VERSION 5.7 ;
  NOWIREEXTENSIONATPIN ON ;
  DIVIDERCHAR "/" ;
  BUSBITCHARS "[]" ;
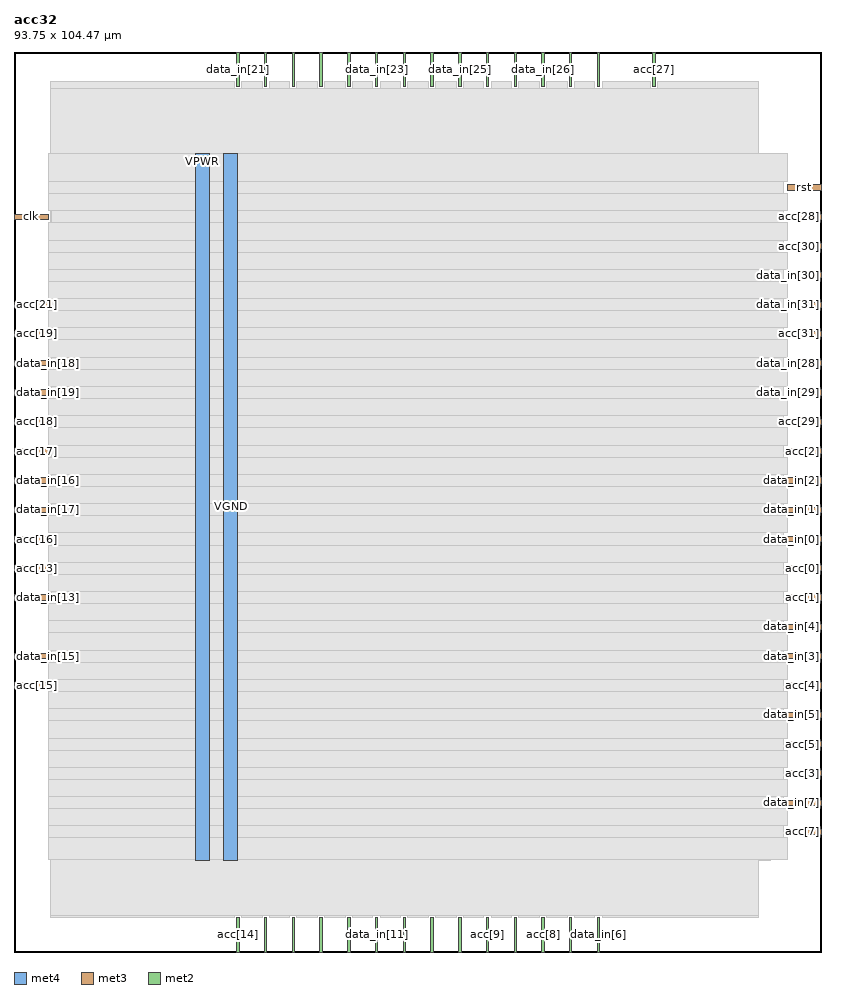
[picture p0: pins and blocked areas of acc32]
MACRO acc32
  CLASS BLOCK ;
  FOREIGN acc32 ;
  ORIGIN 0.000 0.000 ;
  SIZE 93.750 BY 104.470 ;
  PIN VGND
    DIRECTION INOUT ;
    USE GROUND ;
    PORT
      LAYER met4 ;
        RECT 24.340 10.640 25.940 92.720 ;
    END
  END VGND
  PIN VPWR
    DIRECTION INOUT ;
    USE POWER ;
    PORT
      LAYER met4 ;
        RECT 21.040 10.640 22.640 92.720 ;
    END
  END VPWR
  PIN acc[0]
    DIRECTION OUTPUT ;
    USE SIGNAL ;
    ANTENNADIFFAREA 0.445500 ;
    PORT
      LAYER met3 ;
        RECT 89.750 44.240 93.750 44.840 ;
    END
  END acc[0]
  PIN acc[10]
    DIRECTION OUTPUT ;
    USE SIGNAL ;
    ANTENNADIFFAREA 0.445500 ;
    PORT
      LAYER met2 ;
        RECT 35.510 0.000 35.790 4.000 ;
    END
  END acc[10]
  PIN acc[11]
    DIRECTION OUTPUT ;
    USE SIGNAL ;
    ANTENNADIFFAREA 0.445500 ;
    PORT
      LAYER met2 ;
        RECT 45.170 0.000 45.450 4.000 ;
    END
  END acc[11]
  PIN acc[12]
    DIRECTION OUTPUT ;
    USE SIGNAL ;
    ANTENNADIFFAREA 0.445500 ;
    PORT
      LAYER met2 ;
        RECT 48.390 0.000 48.670 4.000 ;
    END
  END acc[12]
  PIN acc[13]
    DIRECTION OUTPUT ;
    USE SIGNAL ;
    ANTENNADIFFAREA 0.445500 ;
    PORT
      LAYER met3 ;
        RECT 0.000 44.240 4.000 44.840 ;
    END
  END acc[13]
  PIN acc[14]
    DIRECTION OUTPUT ;
    USE SIGNAL ;
    ANTENNADIFFAREA 0.445500 ;
    PORT
      LAYER met2 ;
        RECT 25.850 0.000 26.130 4.000 ;
    END
  END acc[14]
  PIN acc[15]
    DIRECTION OUTPUT ;
    USE SIGNAL ;
    ANTENNADIFFAREA 0.445500 ;
    PORT
      LAYER met3 ;
        RECT 0.000 30.640 4.000 31.240 ;
    END
  END acc[15]
  PIN acc[16]
    DIRECTION OUTPUT ;
    USE SIGNAL ;
    ANTENNADIFFAREA 0.445500 ;
    PORT
      LAYER met3 ;
        RECT 0.000 47.640 4.000 48.240 ;
    END
  END acc[16]
  PIN acc[17]
    DIRECTION OUTPUT ;
    USE SIGNAL ;
    ANTENNADIFFAREA 0.445500 ;
    PORT
      LAYER met3 ;
        RECT 0.000 57.840 4.000 58.440 ;
    END
  END acc[17]
  PIN acc[18]
    DIRECTION OUTPUT ;
    USE SIGNAL ;
    ANTENNADIFFAREA 0.445500 ;
    PORT
      LAYER met3 ;
        RECT 0.000 61.240 4.000 61.840 ;
    END
  END acc[18]
  PIN acc[19]
    DIRECTION OUTPUT ;
    USE SIGNAL ;
    ANTENNADIFFAREA 0.445500 ;
    PORT
      LAYER met3 ;
        RECT 0.000 71.440 4.000 72.040 ;
    END
  END acc[19]
  PIN acc[1]
    DIRECTION OUTPUT ;
    USE SIGNAL ;
    ANTENNADIFFAREA 0.445500 ;
    PORT
      LAYER met3 ;
        RECT 89.750 40.840 93.750 41.440 ;
    END
  END acc[1]
  PIN acc[20]
    DIRECTION OUTPUT ;
    USE SIGNAL ;
    ANTENNADIFFAREA 0.445500 ;
    PORT
      LAYER met2 ;
        RECT 35.510 100.470 35.790 104.470 ;
    END
  END acc[20]
  PIN acc[21]
    DIRECTION OUTPUT ;
    USE SIGNAL ;
    ANTENNADIFFAREA 0.445500 ;
    PORT
      LAYER met3 ;
        RECT 0.000 74.840 4.000 75.440 ;
    END
  END acc[21]
  PIN acc[22]
    DIRECTION OUTPUT ;
    USE SIGNAL ;
    ANTENNADIFFAREA 0.445500 ;
    PORT
      LAYER met2 ;
        RECT 29.070 100.470 29.350 104.470 ;
    END
  END acc[22]
  PIN acc[23]
    DIRECTION OUTPUT ;
    USE SIGNAL ;
    ANTENNADIFFAREA 0.445500 ;
    PORT
      LAYER met2 ;
        RECT 45.170 100.470 45.450 104.470 ;
    END
  END acc[23]
  PIN acc[24]
    DIRECTION OUTPUT ;
    USE SIGNAL ;
    ANTENNADIFFAREA 0.445500 ;
    PORT
      LAYER met2 ;
        RECT 54.830 100.470 55.110 104.470 ;
    END
  END acc[24]
  PIN acc[25]
    DIRECTION OUTPUT ;
    USE SIGNAL ;
    ANTENNADIFFAREA 0.445500 ;
    PORT
      LAYER met2 ;
        RECT 48.390 100.470 48.670 104.470 ;
    END
  END acc[25]
  PIN acc[26]
    DIRECTION OUTPUT ;
    USE SIGNAL ;
    ANTENNADIFFAREA 0.445500 ;
    PORT
      LAYER met2 ;
        RECT 67.710 100.470 67.990 104.470 ;
    END
  END acc[26]
  PIN acc[27]
    DIRECTION OUTPUT ;
    USE SIGNAL ;
    ANTENNADIFFAREA 0.445500 ;
    PORT
      LAYER met2 ;
        RECT 74.150 100.470 74.430 104.470 ;
    END
  END acc[27]
  PIN acc[28]
    DIRECTION OUTPUT ;
    USE SIGNAL ;
    ANTENNADIFFAREA 0.445500 ;
    PORT
      LAYER met3 ;
        RECT 89.750 85.040 93.750 85.640 ;
    END
  END acc[28]
  PIN acc[29]
    DIRECTION OUTPUT ;
    USE SIGNAL ;
    ANTENNADIFFAREA 0.445500 ;
    PORT
      LAYER met3 ;
        RECT 89.750 61.240 93.750 61.840 ;
    END
  END acc[29]
  PIN acc[2]
    DIRECTION OUTPUT ;
    USE SIGNAL ;
    ANTENNADIFFAREA 0.445500 ;
    PORT
      LAYER met3 ;
        RECT 89.750 57.840 93.750 58.440 ;
    END
  END acc[2]
  PIN acc[30]
    DIRECTION OUTPUT ;
    USE SIGNAL ;
    ANTENNADIFFAREA 0.445500 ;
    PORT
      LAYER met3 ;
        RECT 89.750 81.640 93.750 82.240 ;
    END
  END acc[30]
  PIN acc[31]
    DIRECTION OUTPUT ;
    USE SIGNAL ;
    ANTENNADIFFAREA 0.445500 ;
    PORT
      LAYER met3 ;
        RECT 89.750 71.440 93.750 72.040 ;
    END
  END acc[31]
  PIN acc[3]
    DIRECTION OUTPUT ;
    USE SIGNAL ;
    ANTENNADIFFAREA 0.445500 ;
    PORT
      LAYER met3 ;
        RECT 89.750 20.440 93.750 21.040 ;
    END
  END acc[3]
  PIN acc[4]
    DIRECTION OUTPUT ;
    USE SIGNAL ;
    ANTENNADIFFAREA 0.445500 ;
    PORT
      LAYER met3 ;
        RECT 89.750 30.640 93.750 31.240 ;
    END
  END acc[4]
  PIN acc[5]
    DIRECTION OUTPUT ;
    USE SIGNAL ;
    ANTENNADIFFAREA 0.445500 ;
    PORT
      LAYER met3 ;
        RECT 89.750 23.840 93.750 24.440 ;
    END
  END acc[5]
  PIN acc[6]
    DIRECTION OUTPUT ;
    USE SIGNAL ;
    ANTENNADIFFAREA 0.445500 ;
    PORT
      LAYER met2 ;
        RECT 64.490 0.000 64.770 4.000 ;
    END
  END acc[6]
  PIN acc[7]
    DIRECTION OUTPUT ;
    USE SIGNAL ;
    ANTENNADIFFAREA 0.445500 ;
    PORT
      LAYER met3 ;
        RECT 89.750 13.640 93.750 14.240 ;
    END
  END acc[7]
  PIN acc[8]
    DIRECTION OUTPUT ;
    USE SIGNAL ;
    ANTENNADIFFAREA 0.445500 ;
    PORT
      LAYER met2 ;
        RECT 61.270 0.000 61.550 4.000 ;
    END
  END acc[8]
  PIN acc[9]
    DIRECTION OUTPUT ;
    USE SIGNAL ;
    ANTENNADIFFAREA 0.445500 ;
    PORT
      LAYER met2 ;
        RECT 54.830 0.000 55.110 4.000 ;
    END
  END acc[9]
  PIN clk
    DIRECTION INPUT ;
    USE SIGNAL ;
    ANTENNAGATEAREA 0.852000 ;
    PORT
      LAYER met3 ;
        RECT 0.000 85.040 4.000 85.640 ;
    END
  END clk
  PIN data_in[0]
    DIRECTION INPUT ;
    USE SIGNAL ;
    ANTENNAGATEAREA 0.196500 ;
    PORT
      LAYER met3 ;
        RECT 89.750 47.640 93.750 48.240 ;
    END
  END data_in[0]
  PIN data_in[10]
    DIRECTION INPUT ;
    USE SIGNAL ;
    ANTENNAGATEAREA 0.196500 ;
    PORT
      LAYER met2 ;
        RECT 38.730 0.000 39.010 4.000 ;
    END
  END data_in[10]
  PIN data_in[11]
    DIRECTION INPUT ;
    USE SIGNAL ;
    ANTENNAGATEAREA 0.196500 ;
    PORT
      LAYER met2 ;
        RECT 41.950 0.000 42.230 4.000 ;
    END
  END data_in[11]
  PIN data_in[12]
    DIRECTION INPUT ;
    USE SIGNAL ;
    ANTENNAGATEAREA 0.196500 ;
    PORT
      LAYER met2 ;
        RECT 32.290 0.000 32.570 4.000 ;
    END
  END data_in[12]
  PIN data_in[13]
    DIRECTION INPUT ;
    USE SIGNAL ;
    ANTENNAGATEAREA 0.196500 ;
    PORT
      LAYER met3 ;
        RECT 0.000 40.840 4.000 41.440 ;
    END
  END data_in[13]
  PIN data_in[14]
    DIRECTION INPUT ;
    USE SIGNAL ;
    ANTENNAGATEAREA 0.196500 ;
    PORT
      LAYER met2 ;
        RECT 29.070 0.000 29.350 4.000 ;
    END
  END data_in[14]
  PIN data_in[15]
    DIRECTION INPUT ;
    USE SIGNAL ;
    ANTENNAGATEAREA 0.196500 ;
    PORT
      LAYER met3 ;
        RECT 0.000 34.040 4.000 34.640 ;
    END
  END data_in[15]
  PIN data_in[16]
    DIRECTION INPUT ;
    USE SIGNAL ;
    ANTENNAGATEAREA 0.196500 ;
    PORT
      LAYER met3 ;
        RECT 0.000 54.440 4.000 55.040 ;
    END
  END data_in[16]
  PIN data_in[17]
    DIRECTION INPUT ;
    USE SIGNAL ;
    ANTENNAGATEAREA 0.196500 ;
    PORT
      LAYER met3 ;
        RECT 0.000 51.040 4.000 51.640 ;
    END
  END data_in[17]
  PIN data_in[18]
    DIRECTION INPUT ;
    USE SIGNAL ;
    ANTENNAGATEAREA 0.196500 ;
    PORT
      LAYER met3 ;
        RECT 0.000 68.040 4.000 68.640 ;
    END
  END data_in[18]
  PIN data_in[19]
    DIRECTION INPUT ;
    USE SIGNAL ;
    ANTENNAGATEAREA 0.196500 ;
    PORT
      LAYER met3 ;
        RECT 0.000 64.640 4.000 65.240 ;
    END
  END data_in[19]
  PIN data_in[1]
    DIRECTION INPUT ;
    USE SIGNAL ;
    ANTENNAGATEAREA 0.196500 ;
    PORT
      LAYER met3 ;
        RECT 89.750 51.040 93.750 51.640 ;
    END
  END data_in[1]
  PIN data_in[20]
    DIRECTION INPUT ;
    USE SIGNAL ;
    ANTENNAGATEAREA 0.196500 ;
    PORT
      LAYER met2 ;
        RECT 38.730 100.470 39.010 104.470 ;
    END
  END data_in[20]
  PIN data_in[21]
    DIRECTION INPUT ;
    USE SIGNAL ;
    ANTENNAGATEAREA 0.196500 ;
    PORT
      LAYER met2 ;
        RECT 25.850 100.470 26.130 104.470 ;
    END
  END data_in[21]
  PIN data_in[22]
    DIRECTION INPUT ;
    USE SIGNAL ;
    ANTENNAGATEAREA 0.196500 ;
    PORT
      LAYER met2 ;
        RECT 32.290 100.470 32.570 104.470 ;
    END
  END data_in[22]
  PIN data_in[23]
    DIRECTION INPUT ;
    USE SIGNAL ;
    ANTENNAGATEAREA 0.196500 ;
    PORT
      LAYER met2 ;
        RECT 41.950 100.470 42.230 104.470 ;
    END
  END data_in[23]
  PIN data_in[24]
    DIRECTION INPUT ;
    USE SIGNAL ;
    ANTENNAGATEAREA 0.196500 ;
    PORT
      LAYER met2 ;
        RECT 58.050 100.470 58.330 104.470 ;
    END
  END data_in[24]
  PIN data_in[25]
    DIRECTION INPUT ;
    USE SIGNAL ;
    ANTENNAGATEAREA 0.196500 ;
    PORT
      LAYER met2 ;
        RECT 51.610 100.470 51.890 104.470 ;
    END
  END data_in[25]
  PIN data_in[26]
    DIRECTION INPUT ;
    USE SIGNAL ;
    ANTENNAGATEAREA 0.196500 ;
    PORT
      LAYER met2 ;
        RECT 61.270 100.470 61.550 104.470 ;
    END
  END data_in[26]
  PIN data_in[27]
    DIRECTION INPUT ;
    USE SIGNAL ;
    ANTENNAGATEAREA 0.196500 ;
    PORT
      LAYER met2 ;
        RECT 64.490 100.470 64.770 104.470 ;
    END
  END data_in[27]
  PIN data_in[28]
    DIRECTION INPUT ;
    USE SIGNAL ;
    ANTENNAGATEAREA 0.196500 ;
    PORT
      LAYER met3 ;
        RECT 89.750 68.040 93.750 68.640 ;
    END
  END data_in[28]
  PIN data_in[29]
    DIRECTION INPUT ;
    USE SIGNAL ;
    ANTENNAGATEAREA 0.196500 ;
    PORT
      LAYER met3 ;
        RECT 89.750 64.640 93.750 65.240 ;
    END
  END data_in[29]
  PIN data_in[2]
    DIRECTION INPUT ;
    USE SIGNAL ;
    ANTENNAGATEAREA 0.196500 ;
    PORT
      LAYER met3 ;
        RECT 89.750 54.440 93.750 55.040 ;
    END
  END data_in[2]
  PIN data_in[30]
    DIRECTION INPUT ;
    USE SIGNAL ;
    ANTENNAGATEAREA 0.196500 ;
    PORT
      LAYER met3 ;
        RECT 89.750 78.240 93.750 78.840 ;
    END
  END data_in[30]
  PIN data_in[31]
    DIRECTION INPUT ;
    USE SIGNAL ;
    ANTENNAGATEAREA 0.196500 ;
    PORT
      LAYER met3 ;
        RECT 89.750 74.840 93.750 75.440 ;
    END
  END data_in[31]
  PIN data_in[3]
    DIRECTION INPUT ;
    USE SIGNAL ;
    ANTENNAGATEAREA 0.213000 ;
    PORT
      LAYER met3 ;
        RECT 89.750 34.040 93.750 34.640 ;
    END
  END data_in[3]
  PIN data_in[4]
    DIRECTION INPUT ;
    USE SIGNAL ;
    ANTENNAGATEAREA 0.196500 ;
    PORT
      LAYER met3 ;
        RECT 89.750 37.440 93.750 38.040 ;
    END
  END data_in[4]
  PIN data_in[5]
    DIRECTION INPUT ;
    USE SIGNAL ;
    ANTENNAGATEAREA 0.196500 ;
    PORT
      LAYER met3 ;
        RECT 89.750 27.240 93.750 27.840 ;
    END
  END data_in[5]
  PIN data_in[6]
    DIRECTION INPUT ;
    USE SIGNAL ;
    ANTENNAGATEAREA 0.196500 ;
    PORT
      LAYER met2 ;
        RECT 67.710 0.000 67.990 4.000 ;
    END
  END data_in[6]
  PIN data_in[7]
    DIRECTION INPUT ;
    USE SIGNAL ;
    ANTENNAGATEAREA 0.196500 ;
    PORT
      LAYER met3 ;
        RECT 89.750 17.040 93.750 17.640 ;
    END
  END data_in[7]
  PIN data_in[8]
    DIRECTION INPUT ;
    USE SIGNAL ;
    ANTENNAGATEAREA 0.196500 ;
    PORT
      LAYER met2 ;
        RECT 58.050 0.000 58.330 4.000 ;
    END
  END data_in[8]
  PIN data_in[9]
    DIRECTION INPUT ;
    USE SIGNAL ;
    ANTENNAGATEAREA 0.196500 ;
    PORT
      LAYER met2 ;
        RECT 51.610 0.000 51.890 4.000 ;
    END
  END data_in[9]
  PIN rst
    DIRECTION INPUT ;
    USE SIGNAL ;
    ANTENNAGATEAREA 0.196500 ;
    PORT
      LAYER met3 ;
        RECT 89.750 88.440 93.750 89.040 ;
    END
  END rst
  OBS
      LAYER nwell ;
        RECT 5.330 10.795 88.050 92.565 ;
      LAYER li1 ;
        RECT 5.520 10.795 87.860 92.565 ;
      LAYER met1 ;
        RECT 4.210 10.640 87.860 92.720 ;
      LAYER met2 ;
        RECT 4.230 100.190 25.570 101.050 ;
        RECT 26.410 100.190 28.790 101.050 ;
        RECT 29.630 100.190 32.010 101.050 ;
        RECT 32.850 100.190 35.230 101.050 ;
        RECT 36.070 100.190 38.450 101.050 ;
        RECT 39.290 100.190 41.670 101.050 ;
        RECT 42.510 100.190 44.890 101.050 ;
        RECT 45.730 100.190 48.110 101.050 ;
        RECT 48.950 100.190 51.330 101.050 ;
        RECT 52.170 100.190 54.550 101.050 ;
        RECT 55.390 100.190 57.770 101.050 ;
        RECT 58.610 100.190 60.990 101.050 ;
        RECT 61.830 100.190 64.210 101.050 ;
        RECT 65.050 100.190 67.430 101.050 ;
        RECT 68.270 100.190 73.870 101.050 ;
        RECT 74.710 100.190 86.390 101.050 ;
        RECT 4.230 4.280 86.390 100.190 ;
        RECT 4.230 4.000 25.570 4.280 ;
        RECT 26.410 4.000 28.790 4.280 ;
        RECT 29.630 4.000 32.010 4.280 ;
        RECT 32.850 4.000 35.230 4.280 ;
        RECT 36.070 4.000 38.450 4.280 ;
        RECT 39.290 4.000 41.670 4.280 ;
        RECT 42.510 4.000 44.890 4.280 ;
        RECT 45.730 4.000 48.110 4.280 ;
        RECT 48.950 4.000 51.330 4.280 ;
        RECT 52.170 4.000 54.550 4.280 ;
        RECT 55.390 4.000 57.770 4.280 ;
        RECT 58.610 4.000 60.990 4.280 ;
        RECT 61.830 4.000 64.210 4.280 ;
        RECT 65.050 4.000 67.430 4.280 ;
        RECT 68.270 4.000 86.390 4.280 ;
      LAYER met3 ;
        RECT 3.990 89.440 89.750 92.645 ;
        RECT 3.990 88.040 89.350 89.440 ;
        RECT 3.990 86.040 89.750 88.040 ;
        RECT 4.400 84.640 89.350 86.040 ;
        RECT 3.990 82.640 89.750 84.640 ;
        RECT 3.990 81.240 89.350 82.640 ;
        RECT 3.990 79.240 89.750 81.240 ;
        RECT 3.990 77.840 89.350 79.240 ;
        RECT 3.990 75.840 89.750 77.840 ;
        RECT 4.400 74.440 89.350 75.840 ;
        RECT 3.990 72.440 89.750 74.440 ;
        RECT 4.400 71.040 89.350 72.440 ;
        RECT 3.990 69.040 89.750 71.040 ;
        RECT 4.400 67.640 89.350 69.040 ;
        RECT 3.990 65.640 89.750 67.640 ;
        RECT 4.400 64.240 89.350 65.640 ;
        RECT 3.990 62.240 89.750 64.240 ;
        RECT 4.400 60.840 89.350 62.240 ;
        RECT 3.990 58.840 89.750 60.840 ;
        RECT 4.400 57.440 89.350 58.840 ;
        RECT 3.990 55.440 89.750 57.440 ;
        RECT 4.400 54.040 89.350 55.440 ;
        RECT 3.990 52.040 89.750 54.040 ;
        RECT 4.400 50.640 89.350 52.040 ;
        RECT 3.990 48.640 89.750 50.640 ;
        RECT 4.400 47.240 89.350 48.640 ;
        RECT 3.990 45.240 89.750 47.240 ;
        RECT 4.400 43.840 89.350 45.240 ;
        RECT 3.990 41.840 89.750 43.840 ;
        RECT 4.400 40.440 89.350 41.840 ;
        RECT 3.990 38.440 89.750 40.440 ;
        RECT 3.990 37.040 89.350 38.440 ;
        RECT 3.990 35.040 89.750 37.040 ;
        RECT 4.400 33.640 89.350 35.040 ;
        RECT 3.990 31.640 89.750 33.640 ;
        RECT 4.400 30.240 89.350 31.640 ;
        RECT 3.990 28.240 89.750 30.240 ;
        RECT 3.990 26.840 89.350 28.240 ;
        RECT 3.990 24.840 89.750 26.840 ;
        RECT 3.990 23.440 89.350 24.840 ;
        RECT 3.990 21.440 89.750 23.440 ;
        RECT 3.990 20.040 89.350 21.440 ;
        RECT 3.990 18.040 89.750 20.040 ;
        RECT 3.990 16.640 89.350 18.040 ;
        RECT 3.990 14.640 89.750 16.640 ;
        RECT 3.990 13.240 89.350 14.640 ;
        RECT 3.990 10.715 89.750 13.240 ;
  END
END acc32
END LIBRARY

